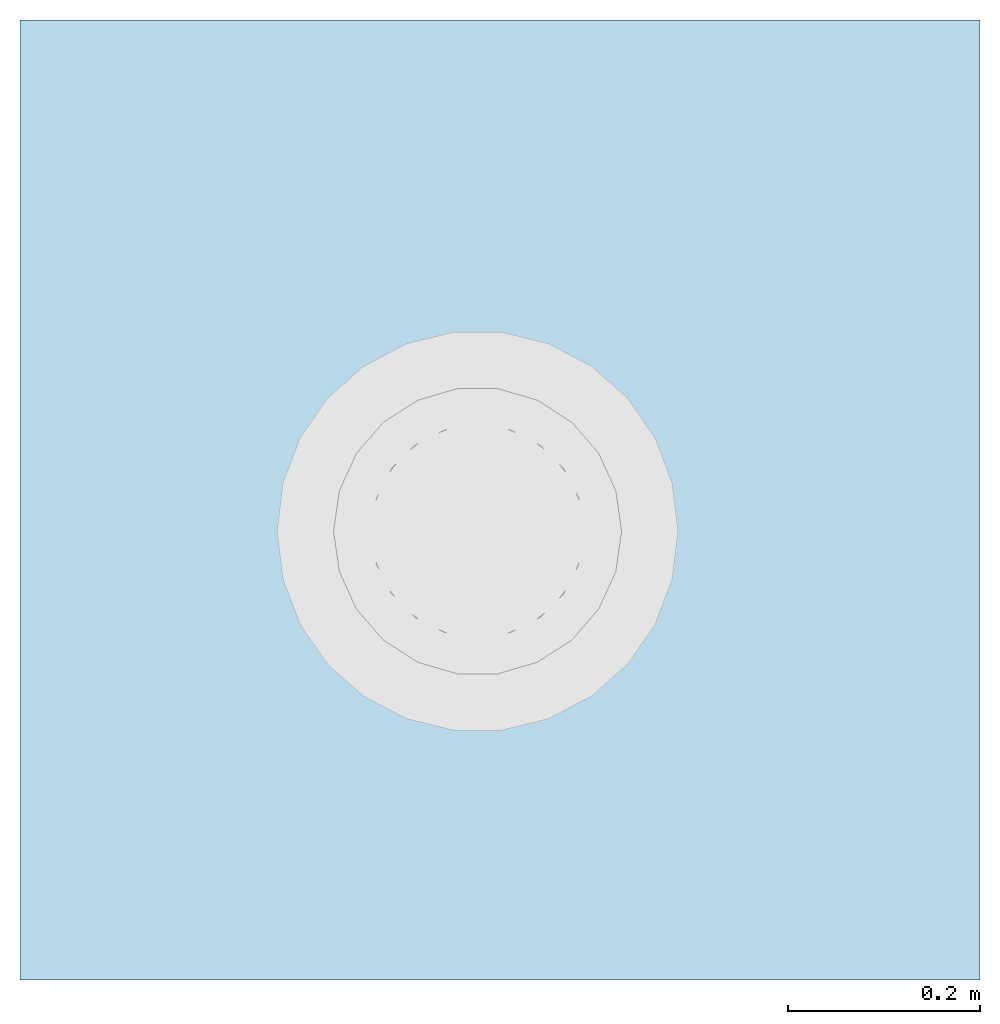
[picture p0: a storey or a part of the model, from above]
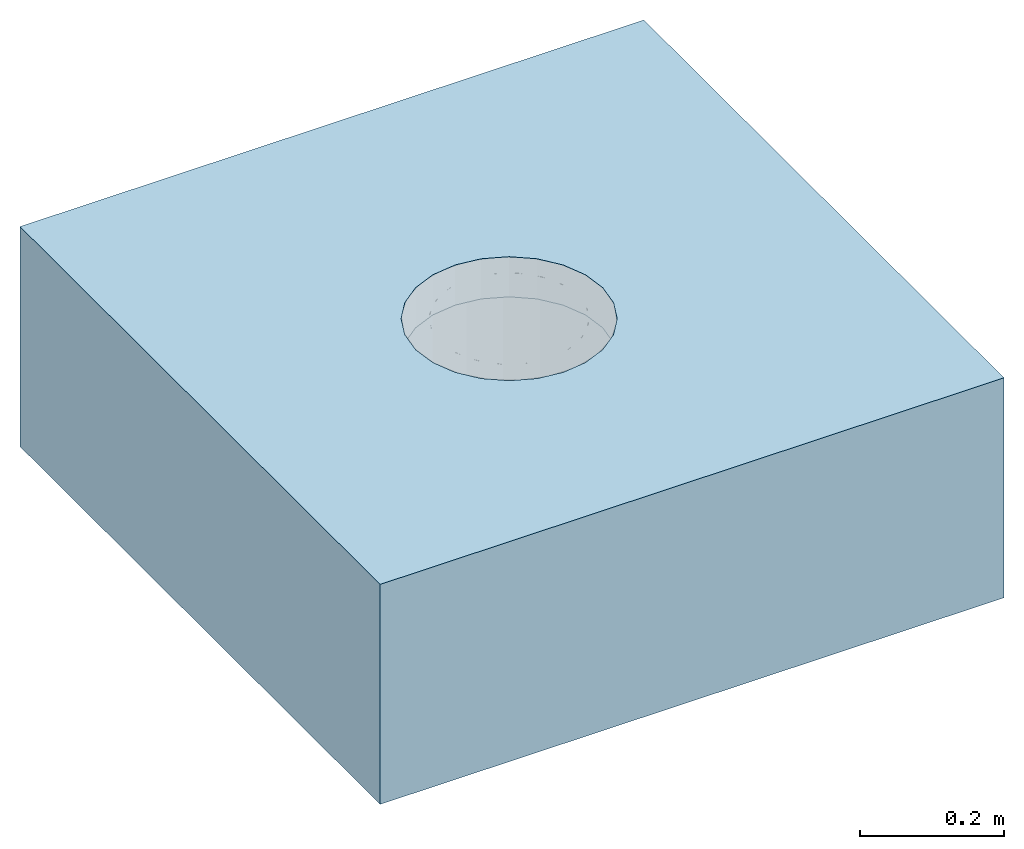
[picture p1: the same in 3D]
Properties of the parts of a building model (IFC2X3)

# File
Description: ViewDefinition [CoordinationView]
File name: Project Number
Time: 2014-10-21T15:17:03
Written by: The EXPRESS Data Manager Version 5.01.0100.02.64mod : 6 Jun 2012
Made in: 20130308_1515(x64) - Exporter 2014.0.2013.0308 - Default UI
Comment: STEP Physical File produced by: The EXPRESS Data Manager Version 5.01.0100.02.64mod : 6 Jun 2012 * Module: EDMstepFileFactory/EDMstandAlone * Creation date: Tue Oct 21 15:17:03 2014 * Host: IN-BLR-PC-0012 * Database: C:\Users\pponnur\AppData\Local\Temp\{2EB973AC-0FA0-435C-9EAB-D43C870D9FF9}\ifc * Database version: 5507 * Database creation date: Tue Oct 21 15:17:02 2014 * Schema: IFC2X3 * Model: DataRepository.ifc * Model creation date: Tue Oct 21 15:17:02 2014 * Header model: DataRepository.ifc_HeaderModel * Header model creation date: Tue Oct 21 15:17:02 2014 * EDMuser: sdai-user * EDMgroup: sdai-group * License ID and type: 5605 : Permanent license. Expiry date: * EDMstepFileFactory options: 020000

# IfcProject, Project Number
LongName: Project Name; Phase: Project Status

# IfcSite, Default
RefLatitude: 42, 21, 30, 344238; RefLongitude: -71, -3, -35, -194702; RefElevation: 0 mm

# IfcBuilding
Pset_BuildingCommon - NumberOfStoreys: 1
Other - Project Address: Enter address here; Project Status: Project Status; Project Number: Project Number; Project Issue Date: Issue Date; Client Name: Owner; Project Name: Project Name

# IfcBuildingStorey, Level 1
LongName: Level 1; Elevation: 0 mm
Graphics - Symbol at End 1 Default: no; Symbol: Level Head - Circle: Level Head - Circle; Symbol at End 2 Default: yes; Line Pattern: Grid Line 1/2"; Color: 0; Line Weight: 1
Constraints - Elevation Base: Project Base Point; Elevation: 0 mm
Identity Data - Structural: no; Name: Level 1; Building Story: yes
Dimensions - Computation Height: 0 mm

# IfcFlowTerminal: 408065 Body / 408242 Top - 110mm Dia Outlet, ACO BD Gully 218 Telescopic - Vinyl top - Vertical Outlet with Mechanical Flange - 222 mm:408065 Body / 408242 Top - 110mm Dia Outlet:220497
In: Level 1
Material: Rubber, Nitrile, Stainless Steel AISI 304
Identity Data - Water Mark 1: This file is the property of ACO Technologies PLC; Telephone: +44 (0)1462 816666; E-mail Sales: abdcommercial@aco.co.uk; E-mail Technical: abdtechnical@aco.co.uk; Water Marked With: BIM Manager Premium Suite; Fax: +44 (0)1462 851490; Water Mark 2: This file is water marked and users are prohibited to reproduce, adapt, distribute this information; Address: ACO Business Centre, Caxton Road, Bedford, MK41 0LF; Website: www.acobd.com; Manufacturer: ACO Building Drainage; Watermarked By: www.acobd.com; Mark: 12
Other - Floor to Gully Height: 68 mm; 408227 - Raising piece with Mechanical Clamping flange: no; Floor Void End: -238 mm; Raising Piece Detail: no; Gully Void Start: 0 mm; Raising Piece Position Height: 500 mm; Gully Top: yes; Grating 250 x 250mm: yes; Vertical 160: no; vertical 110: yes
Construction - 97153 - 222mm Ø - Perforated Grating - Plain - Stainless steel 304: no; 408222 - Silt Basket: yes; 97156 - 222mm Ø - Slot Grating - Plain - Stainless steel 304: no; 97148 - 222mm Ø - Ladder Grating - Plain - Stainless steel 304: no; 408220 - Foul Air Trap & 408221 - Foul Air Trap Support Ring: yes
Mechanical - System Classification: Sanitary
Model Properties - Raising Piece Product Code 408227: NA; Product Code 408221: Foul Air Trap Support Ring - Nitrile; Product Code 408220: Foul Air Trap - Stainless Steel 304; Product Code 408222: Silt Basket - Stainless Steel 304; Grating Product Code 97156: Load Class M125 (EN 1253) - Slot Grating - Plain - Stainless steel 1.4301 (EN 10088) - 222mm Ø; Grating Product Code 97153: Load Class L15 (EN 1253) - Perforated Grating - Plain - Stainless steel 1.4301 (EN 10088) - 222mm Ø; Grating Product Code 97148: Load Class M125 (EN 1253) - Ladder Grating - Plain - Stainless steel 1.4301 (EN 10088) - 222mm Ø; Product Code 408225: Friction Ring Installation Set - Nitrile
Phasing - Phase Created: New Construction
Constraints - Level: Level: Level 1
Dimensions - FFL To Gully Top Height: 68 mm; Seepage Water Removal Pipe End: -25 mm; Outlet Height: 98 mm; Square Size: 300 mm; Grating Depth: 30 mm; Outlet: 53.5 mm; Gully Void End: -268 mm
Pset_ManufacturerTypeInformation - Manufacturer: ACO Building Drainage
General - Load Class: A15 - C250 (EN 1253); Product Type: Point Drainage; Installation guidelines: http://issuu.com/acobuildingdrainage/docs/120820112708-138bdc871b784edfa2b6b8197acfd881?e=0; Gully Product Code: 408065; Gully Recycled Material Content: 20 - 30 %; Gully Product Description: ACO Gully 218 Telescopic Flange Type DN110 Vertical with Foul Air Trap; Outlet Diameter (mm): 110; Gully Top Product Code: 408242; Gully Top Product Description: ACO Gully 218 Telescopic Top for Vinyl Floor; Foul Air Trap Seal Material: NBR; Product Range: ACO Gully 218; Gully Flange Type: Mechanical; Flow Rate (l/s): 5.0 - 6.3 l/s; Foul Air Trap Seal Recycled Material Content: 0%; Gully Top Size (mm): 242mm Diameter; Product Standard: EN 1253; Maintenance guidelines: http://issuu.com/acobuildingdrainage/docs/120820112708-138bdc871b784edfa2b6b8197acfd881?e=0; Price: POA - contact ACO; Gully top Grate size (mm): 222; Foul Air Trap Seal Recyclable: Fully Recyclable; Gully Material: Stainless Steel Grade 304 (EN 1253); Foul Air Trap Seal Colour: Black; NBS Specification: R11 ABOVE GROUND FOUL DRAINAGE SYSTEMS : Clause 315; Gully Recyclable: Fully Recyclable; Gully Colour: passivated stainless steel surface ( matt grey)
Materials and Finishes - Material: Stainless Steel AISI 304

# IfcOpeningElement: Recess
In: Level 1
Dimensions - Perimeter: 4000 mm; Volume: 11.653 ft3; Thickness: 372.8 mm; Area: 10.7639 ft2
Phasing - Phase Created: New Construction
Constraints - Room Bounding: yes; Related to Mass: no; Height Offset From Level: 0 mm; Level: Level: Level 1
Structural - Structural: no; Enable Analytical Model: no
Identity Data - Assembly Code: B1010; Assembly Description: Floor Construction
Analytical Properties - Absorptance: 0.7; Heat Transfer Coefficient (U): 1.55882; Roughness: 3; Thermal mass: 53301.1; Thermal Resistance (R): 0.641509
Graphics - Coarse Scale Fill Color: 0
Construction - Function: Interior; Default Thickness: 372.8 mm

# IfcSlab: Floor:Generic - 12", Floor:Generic - 12":184145
In: Level 1
PredefinedType: FLOOR; Material: Plywood, Sheathing 68 mm, Default Floor 304.8 mm
Dimensions - Perimeter: 4000 mm; Volume: 11.653 ft3; Thickness: 372.8 mm; Area: 10.7639 ft2
Phasing - Phase Created: New Construction
Constraints - Room Bounding: yes; Related to Mass: no; Height Offset From Level: 0 mm; Level: Level: Level 1
Structural - Structural: no; Enable Analytical Model: no
Pset_SlabCommon - Reference: Generic - 12"; IsExternal: no; LoadBearing: yes; ThermalTransmittance: 1.55882 kg/K/s3
Identity Data - Assembly Code: B1010; Assembly Description: Floor Construction
Analytical Properties - Absorptance: 0.7; Heat Transfer Coefficient (U): 1.55882; Roughness: 3; Thermal mass: 53301.1; Thermal Resistance (R): 0.641509
Graphics - Coarse Scale Fill Color: 0
Construction - Function: Interior; Default Thickness: 372.8 mm
